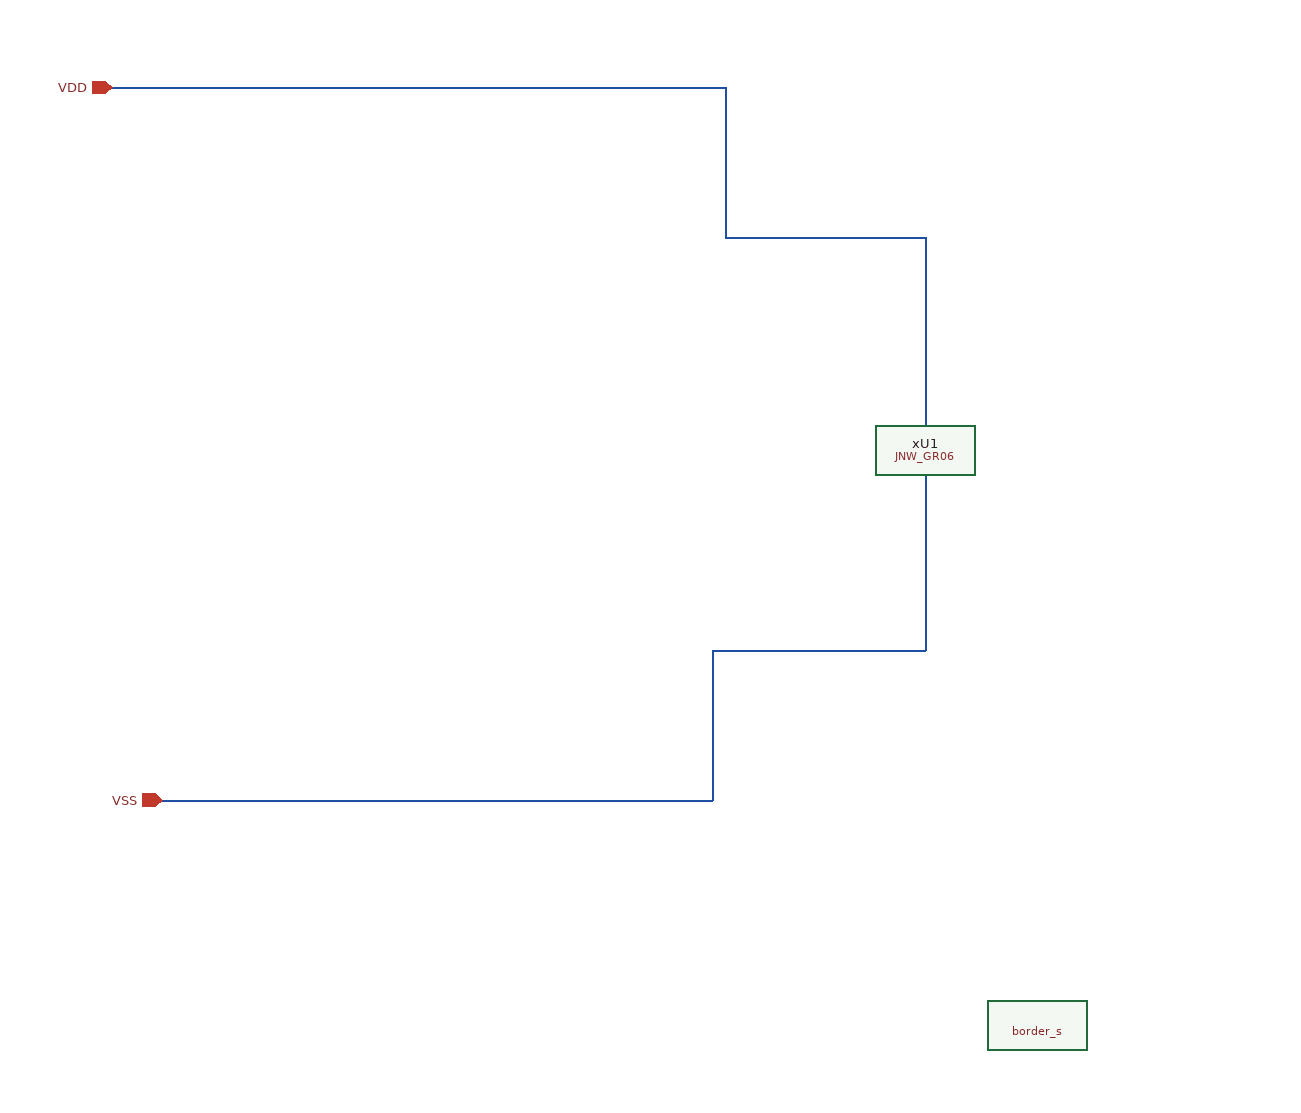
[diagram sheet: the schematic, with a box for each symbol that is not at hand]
v {xschem version=3.4.6 file_version=1.2}
G {}
K {}
V {}
S {}
E {}
N 740 -880 1230 -880 {lab=VDD}
N 780 -310 1020 -310 {lab=VSS}
N 1220 -430 1390 -430 {lab=VSS}
N 1020 -310 1220 -310 {
lab=VSS}
N 1220 -430 1220 -310 {
lab=VSS}
N 1230 -880 1230 -760 {
lab=VDD}
N 1230 -760 1390 -760 {
lab=VDD}
N 1390 -760 1390 -700 {lab=VDD}
N 1390 -490 1390 -430 {lab=VSS}
N 1390 -700 1390 -610 {lab=VDD}
N 1390 -570 1390 -490 {lab=VSS}
C {cborder/border_s.sym} 1480 -130 0 0 {
user="bkle"
company="bkle"}
C {devices/ipin.sym} 740 -880 0 0 {name=p3 lab=VDD}
C {devices/ipin.sym} 780 -310 0 0 {name=p5 lab=VSS}
C {JNW_BKLE_SKY130A/JNW_GR06.sym} 1540 -590 0 0 {name=xU1}
